VERSION 5.7 ;
  NOWIREEXTENSIONATPIN ON ;
  DIVIDERCHAR "/" ;
  BUSBITCHARS "[]" ;
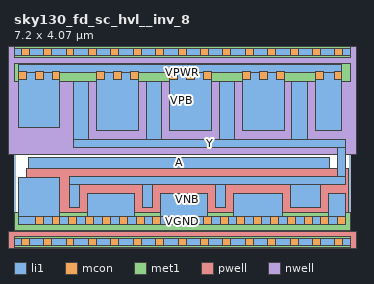
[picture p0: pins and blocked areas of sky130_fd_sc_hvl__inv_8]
MACRO sky130_fd_sc_hvl__inv_8
  CLASS BLOCK ;
  FOREIGN sky130_fd_sc_hvl__inv_8 ;
  ORIGIN 0.000 0.000 ;
  SIZE 7.200 BY 4.070 ;
  PIN A
    ANTENNAGATEAREA 9.000000 ;
    PORT
      LAYER li1 ;
        RECT 0.310 1.580 6.760 1.815 ;
    END
  END A
  PIN VGND
    USE GROUND ;
    PORT
      LAYER li1 ;
        RECT 0.095 0.550 0.985 1.385 ;
        RECT 1.575 0.550 2.585 1.045 ;
        RECT 3.135 0.550 4.145 1.045 ;
        RECT 4.695 0.550 5.745 1.045 ;
        RECT 6.735 0.550 7.105 1.045 ;
        RECT 0.095 0.380 7.105 0.550 ;
      LAYER mcon ;
        RECT 0.455 0.380 0.625 0.550 ;
        RECT 0.815 0.380 0.985 0.550 ;
        RECT 1.175 0.380 1.345 0.550 ;
        RECT 1.535 0.380 1.705 0.550 ;
        RECT 1.895 0.380 2.065 0.550 ;
        RECT 2.255 0.380 2.425 0.550 ;
        RECT 2.615 0.380 2.785 0.550 ;
        RECT 2.975 0.380 3.145 0.550 ;
        RECT 3.335 0.380 3.505 0.550 ;
        RECT 3.695 0.380 3.865 0.550 ;
        RECT 4.055 0.380 4.225 0.550 ;
        RECT 4.415 0.380 4.585 0.550 ;
        RECT 4.775 0.380 4.945 0.550 ;
        RECT 5.135 0.380 5.305 0.550 ;
        RECT 5.495 0.380 5.665 0.550 ;
        RECT 5.855 0.380 6.025 0.550 ;
        RECT 6.215 0.380 6.385 0.550 ;
        RECT 6.575 0.380 6.745 0.550 ;
        RECT 6.935 0.380 7.105 0.550 ;
      LAYER met1 ;
        RECT 0.000 0.255 7.200 0.625 ;
    END
  END VGND
  PIN VNB
    ANTENNADIFFAREA 1.224000 ;
    PORT
      LAYER pwell ;
        RECT 0.265 0.215 7.165 1.585 ;
        RECT -0.130 -0.215 7.330 0.215 ;
      LAYER li1 ;
        RECT 0.000 -0.085 7.200 0.085 ;
      LAYER mcon ;
        RECT 0.155 -0.085 0.325 0.085 ;
        RECT 0.635 -0.085 0.805 0.085 ;
        RECT 1.115 -0.085 1.285 0.085 ;
        RECT 1.595 -0.085 1.765 0.085 ;
        RECT 2.075 -0.085 2.245 0.085 ;
        RECT 2.555 -0.085 2.725 0.085 ;
        RECT 3.035 -0.085 3.205 0.085 ;
        RECT 3.515 -0.085 3.685 0.085 ;
        RECT 3.995 -0.085 4.165 0.085 ;
        RECT 4.475 -0.085 4.645 0.085 ;
        RECT 4.955 -0.085 5.125 0.085 ;
        RECT 5.435 -0.085 5.605 0.085 ;
        RECT 5.915 -0.085 6.085 0.085 ;
        RECT 6.395 -0.085 6.565 0.085 ;
        RECT 6.875 -0.085 7.045 0.085 ;
      LAYER met1 ;
        RECT 0.000 -0.115 7.200 0.115 ;
    END
  END VNB
  PIN VPB
    ANTENNADIFFAREA 1.224000 ;
    PORT
      LAYER nwell ;
        RECT -0.330 1.885 7.530 4.485 ;
      LAYER li1 ;
        RECT 0.000 3.985 7.200 4.155 ;
      LAYER mcon ;
        RECT 0.155 3.985 0.325 4.155 ;
        RECT 0.635 3.985 0.805 4.155 ;
        RECT 1.115 3.985 1.285 4.155 ;
        RECT 1.595 3.985 1.765 4.155 ;
        RECT 2.075 3.985 2.245 4.155 ;
        RECT 2.555 3.985 2.725 4.155 ;
        RECT 3.035 3.985 3.205 4.155 ;
        RECT 3.515 3.985 3.685 4.155 ;
        RECT 3.995 3.985 4.165 4.155 ;
        RECT 4.475 3.985 4.645 4.155 ;
        RECT 4.955 3.985 5.125 4.155 ;
        RECT 5.435 3.985 5.605 4.155 ;
        RECT 5.915 3.985 6.085 4.155 ;
        RECT 6.395 3.985 6.565 4.155 ;
        RECT 6.875 3.985 7.045 4.155 ;
      LAYER met1 ;
        RECT 0.000 3.955 7.200 4.185 ;
    END
  END VPB
  PIN VPWR
    USE POWER ;
    PORT
      LAYER li1 ;
        RECT 0.095 3.625 7.025 3.795 ;
        RECT 0.095 2.445 0.985 3.625 ;
        RECT 1.775 2.385 2.665 3.625 ;
        RECT 3.335 2.385 4.225 3.625 ;
        RECT 4.895 2.385 5.785 3.625 ;
        RECT 6.455 2.385 7.025 3.625 ;
      LAYER mcon ;
        RECT 0.095 3.475 0.265 3.645 ;
        RECT 0.455 3.475 0.625 3.645 ;
        RECT 0.815 3.475 0.985 3.645 ;
        RECT 1.775 3.475 1.945 3.645 ;
        RECT 2.135 3.475 2.305 3.645 ;
        RECT 2.495 3.475 2.665 3.645 ;
        RECT 3.335 3.475 3.505 3.645 ;
        RECT 3.695 3.475 3.865 3.645 ;
        RECT 4.055 3.475 4.225 3.645 ;
        RECT 4.895 3.475 5.065 3.645 ;
        RECT 5.255 3.475 5.425 3.645 ;
        RECT 5.615 3.475 5.785 3.645 ;
        RECT 6.455 3.475 6.625 3.645 ;
        RECT 6.855 3.475 7.025 3.645 ;
      LAYER met1 ;
        RECT 0.000 3.445 7.200 3.815 ;
    END
  END VPWR
  PIN Y
    ANTENNADIFFAREA 2.520000 ;
    PORT
      LAYER li1 ;
        RECT 1.275 2.205 1.605 3.445 ;
        RECT 2.835 2.205 3.165 3.445 ;
        RECT 4.395 2.205 4.725 3.445 ;
        RECT 5.955 2.205 6.285 3.445 ;
        RECT 1.275 2.035 7.110 2.205 ;
        RECT 1.195 1.395 6.225 1.400 ;
        RECT 6.940 1.395 7.110 2.035 ;
        RECT 1.195 1.230 7.110 1.395 ;
        RECT 1.195 0.730 1.405 1.230 ;
        RECT 2.755 0.730 2.965 1.230 ;
        RECT 4.315 0.730 4.525 1.230 ;
        RECT 5.915 1.225 7.110 1.230 ;
        RECT 5.915 0.730 6.565 1.225 ;
    END
  END Y
END sky130_fd_sc_hvl__inv_8
END LIBRARY

